VERSION 5.8 ;
BUSBITCHARS "[]" ;
DIVIDERCHAR "/" ;

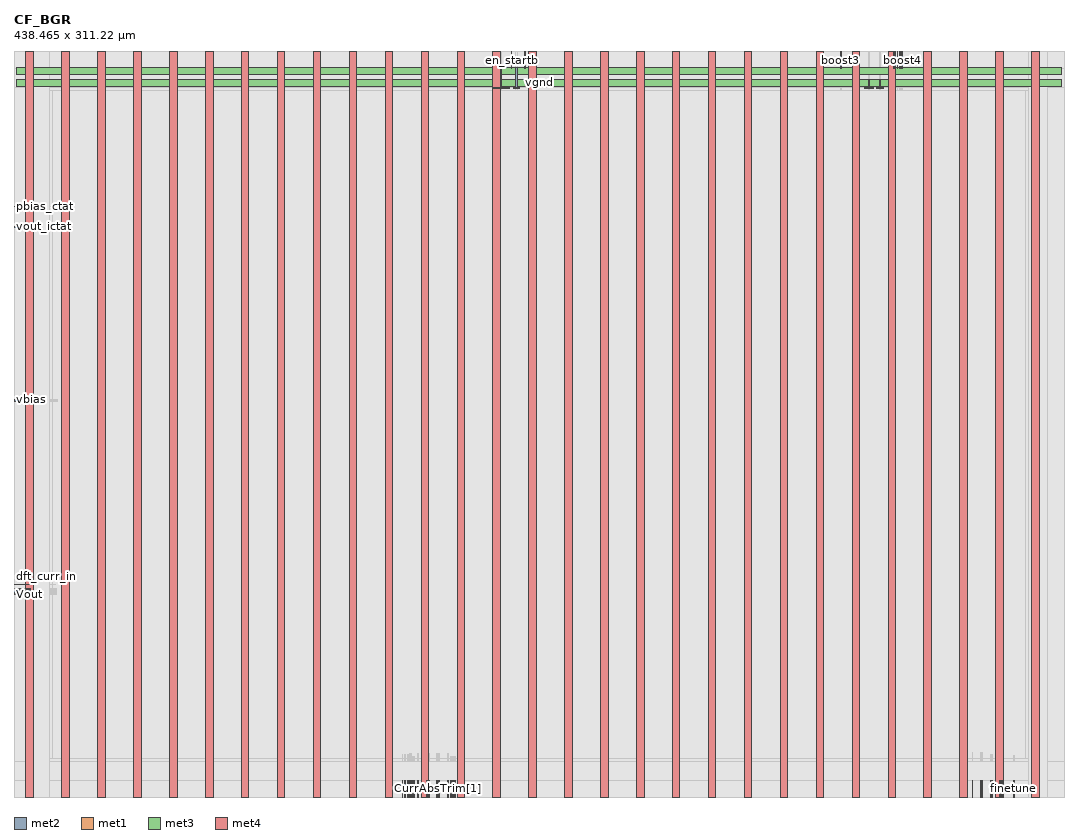
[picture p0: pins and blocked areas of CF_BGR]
MACRO CF_BGR
  CLASS BLOCK ;
  ORIGIN 0 0 ;
  FOREIGN CF_BGR 0 0 ;
  SIZE 438.465 BY 311.22 ;
  PIN CurrAbsTrim[5]
    DIRECTION INPUT ;
    USE SIGNAL ;
    PORT
      LAYER met2 ;
        RECT 181.425 0 181.565 6.9 ;
    END
  END CurrAbsTrim[5]
  PIN finetune
    DIRECTION INPUT ;
    USE SIGNAL ;
    PORT
      LAYER met2 ;
        RECT 417.5 0 417.64 6.9 ;
    END
  END finetune
  PIN boost4
    DIRECTION OUTPUT ;
    USE SIGNAL ;
    PORT
      LAYER met2 ;
        RECT 370.79 304.32 371.11 311.22 ;
    END
  END boost4
  PIN boost7
    DIRECTION OUTPUT ;
    USE SIGNAL ;
    PORT
      LAYER met2 ;
        RECT 369.845 304.32 370.165 311.22 ;
    END
  END boost7
  PIN boost6
    DIRECTION OUTPUT ;
    USE SIGNAL ;
    PORT
      LAYER met2 ;
        RECT 368.765 304.32 369.085 311.22 ;
    END
  END boost6
  PIN boost5
    DIRECTION OUTPUT ;
    USE SIGNAL ;
    PORT
      LAYER met2 ;
        RECT 367.36 304.32 367.68 311.22 ;
    END
  END boost5
  PIN en_startb
    DIRECTION INPUT ;
    USE SIGNAL ;
    PORT
      LAYER met1 ;
        RECT 207.72 304.32 207.86 311.22 ;
    END
  END en_startb
  PIN trimCurr[5]
    DIRECTION INPUT ;
    USE SIGNAL ;
    PORT
      LAYER met2 ;
        RECT 168.295 0 168.435 6.9 ;
    END
  END trimCurr[5]
  PIN trimCurr[4]
    DIRECTION INPUT ;
    USE SIGNAL ;
    PORT
      LAYER met2 ;
        RECT 172.055 0 172.195 6.9 ;
    END
  END trimCurr[4]
  PIN trimCurr[3]
    DIRECTION INPUT ;
    USE SIGNAL ;
    PORT
      LAYER met2 ;
        RECT 172.425 0 172.565 6.9 ;
    END
  END trimCurr[3]
  PIN trimCurr[2]
    DIRECTION INPUT ;
    USE SIGNAL ;
    PORT
      LAYER met2 ;
        RECT 172.795 0 172.935 6.9 ;
    END
  END trimCurr[2]
  PIN trimCurr[0]
    DIRECTION INPUT ;
    USE SIGNAL ;
    PORT
      LAYER met2 ;
        RECT 173.165 0 173.305 6.9 ;
    END
  END trimCurr[0]
  PIN trimCurr[1]
    DIRECTION INPUT ;
    USE SIGNAL ;
    PORT
      LAYER met2 ;
        RECT 176.555 0 176.695 6.9 ;
    END
  END trimCurr[1]
  PIN CurrAbsTrim[0]
    DIRECTION INPUT ;
    USE SIGNAL ;
    PORT
      LAYER met2 ;
        RECT 168.665 0 168.805 6.9 ;
    END
  END CurrAbsTrim[0]
  PIN CurrAbsTrim[1]
    DIRECTION INPUT ;
    USE SIGNAL ;
    PORT
      LAYER met2 ;
        RECT 176.925 0 177.065 6.9 ;
    END
  END CurrAbsTrim[1]
  PIN CurrAbsTrim[2]
    DIRECTION INPUT ;
    USE SIGNAL ;
    PORT
      LAYER met2 ;
        RECT 177.295 0 177.435 6.9 ;
    END
  END CurrAbsTrim[2]
  PIN CurrAbsTrim[3]
    DIRECTION INPUT ;
    USE SIGNAL ;
    PORT
      LAYER met2 ;
        RECT 177.665 0 177.805 6.9 ;
    END
  END CurrAbsTrim[3]
  PIN CurrAbsTrim[4]
    DIRECTION INPUT ;
    USE SIGNAL ;
    PORT
      LAYER met2 ;
        RECT 181.055 0 181.195 6.9 ;
    END
  END CurrAbsTrim[4]
  PIN mux2sel
    DIRECTION INPUT ;
    USE SIGNAL ;
    PORT
      LAYER met2 ;
        RECT 182.16 0 182.3 6.9 ;
    END
  END mux2sel
  PIN mux1sel[0]
    DIRECTION INPUT ;
    USE SIGNAL ;
    PORT
      LAYER met2 ;
        RECT 182.53 0 182.67 6.9 ;
    END
  END mux1sel[0]
  PIN mux1sel[1]
    DIRECTION INPUT ;
    USE SIGNAL ;
    PORT
      LAYER met2 ;
        RECT 182.9 0 183.04 6.9 ;
    END
  END mux1sel[1]
  PIN dft_sel
    DIRECTION INPUT ;
    USE SIGNAL ;
    PORT
      LAYER met2 ;
        RECT 183.27 0 183.41 6.9 ;
    END
  END dft_sel
  PIN pd_ibg
    DIRECTION INPUT ;
    USE SIGNAL ;
    PORT
      LAYER met2 ;
        RECT 183.65 0 183.79 6.9 ;
    END
  END pd_ibg
  PIN pd
    DIRECTION INPUT ;
    USE SIGNAL ;
    PORT
      LAYER met2 ;
        RECT 184.095 0 184.235 6.9 ;
    END
  END pd
  PIN trimTC[6]
    DIRECTION INPUT ;
    USE SIGNAL ;
    PORT
      LAYER met2 ;
        RECT 400.145 0 400.285 6.9 ;
    END
  END trimTC[6]
  PIN trimTC[5]
    DIRECTION INPUT ;
    USE SIGNAL ;
    PORT
      LAYER met2 ;
        RECT 403.535 0 403.675 6.9 ;
    END
  END trimTC[5]
  PIN trimTC[4]
    DIRECTION INPUT ;
    USE SIGNAL ;
    PORT
      LAYER met2 ;
        RECT 404.18 0 404.32 6.9 ;
    END
  END trimTC[4]
  PIN trimTC[3]
    DIRECTION INPUT ;
    USE SIGNAL ;
    PORT
      LAYER met2 ;
        RECT 407.57 0 407.71 6.9 ;
    END
  END trimTC[3]
  PIN trimTC[2]
    DIRECTION INPUT ;
    USE SIGNAL ;
    PORT
      LAYER met2 ;
        RECT 408.27 0 408.41 6.9 ;
    END
  END trimTC[2]
  PIN trimTC[0]
    DIRECTION INPUT ;
    USE SIGNAL ;
    PORT
      LAYER met2 ;
        RECT 411.66 0 411.8 6.9 ;
    END
  END trimTC[0]
  PIN trimTC[1]
    DIRECTION INPUT ;
    USE SIGNAL ;
    PORT
      LAYER met2 ;
        RECT 412.535 0 412.675 6.9 ;
    END
  END trimTC[1]
  PIN inl_ctrl[0]
    DIRECTION INPUT ;
    USE SIGNAL ;
    PORT
      LAYER met2 ;
        RECT 165.955 0 166.095 6.9 ;
    END
  END inl_ctrl[0]
  PIN inl_ctrl[1]
    DIRECTION INPUT ;
    USE SIGNAL ;
    PORT
      LAYER met2 ;
        RECT 165.355 0 165.495 6.9 ;
    END
  END inl_ctrl[1]
  PIN vbias_cascode
    DIRECTION OUTPUT ;
    USE SIGNAL ;
    PORT
      LAYER met2 ;
        RECT 0 164.95 6.9 165.19 ;
    END
  END vbias_cascode
  PIN vbias
    DIRECTION OUTPUT ;
    USE SIGNAL ;
    PORT
      LAYER met2 ;
        RECT 0 165.73 6.9 165.97 ;
    END
  END vbias
  PIN boost3
    DIRECTION OUTPUT ;
    USE SIGNAL ;
    PORT
      LAYER met2 ;
        RECT 345.055 304.32 345.375 311.22 ;
    END
  END boost3
  PIN dft_curr_in
    DIRECTION INPUT ;
    USE SIGNAL ;
    PORT
      LAYER met2 ;
        RECT 0 88.62 6.9 88.86 ;
    END
  END dft_curr_in
  PIN vb2_fast
    DIRECTION INPUT ;
    USE SIGNAL ;
    PORT
      LAYER met1 ;
        RECT 213.215 304.32 213.395 311.22 ;
    END
  END vb2_fast
  PIN Vout
    DIRECTION OUTPUT ;
    USE SIGNAL ;
    PORT
      LAYER met2 ;
        RECT 0 84.56 6.9 84.8 ;
    END
  END Vout
  PIN ibg_3uA
    DIRECTION OUTPUT ;
    USE SIGNAL ;
    PORT
      LAYER met2 ;
        RECT 0 85.06 6.9 85.3 ;
    END
  END ibg_3uA
  PIN ibg_2p375uA
    DIRECTION OUTPUT ;
    USE SIGNAL ;
    PORT
      LAYER met2 ;
        RECT 0 85.5 6.9 85.74 ;
    END
  END ibg_2p375uA
  PIN mux1out
    DIRECTION OUTPUT ;
    USE SIGNAL ;
    PORT
      LAYER met2 ;
        RECT 0 86.03 6.9 86.27 ;
    END
  END mux1out
  PIN mux2out
    DIRECTION OUTPUT ;
    USE SIGNAL ;
    PORT
      LAYER met2 ;
        RECT 0 86.825 6.9 87.065 ;
    END
  END mux2out
  PIN ictat
    DIRECTION OUTPUT ;
    USE SIGNAL ;
    PORT
      LAYER met2 ;
        RECT 166.615 0 166.755 6.9 ;
    END
  END ictat
  PIN iptat
    DIRECTION OUTPUT ;
    USE SIGNAL ;
    PORT
      LAYER met2 ;
        RECT 167.22 0 167.36 6.9 ;
    END
  END iptat
  PIN inl_ctrl[6]
    DIRECTION INPUT ;
    USE SIGNAL ;
    PORT
      LAYER met2 ;
        RECT 162.285 0 162.425 6.9 ;
    END
  END inl_ctrl[6]
  PIN inl_ctrl[5]
    DIRECTION INPUT ;
    USE SIGNAL ;
    PORT
      LAYER met2 ;
        RECT 162.9 0 163.04 6.9 ;
    END
  END inl_ctrl[5]
  PIN vgnd
    DIRECTION INPUT ;
    USE GROUND ;
    PORT
      LAYER met1 ;
        RECT 355.21 295.82 358.78 296.22 ;
      LAYER met2 ;
        RECT 356.755 295.82 357.235 299.82 ;
      LAYER met1 ;
        RECT 360.205 295.82 362.975 296.22 ;
      LAYER met2 ;
        RECT 361.35 295.82 361.83 299.82 ;
      LAYER met3 ;
        RECT 1.23 296.72 437.235 299.82 ;
      LAYER met4 ;
        RECT 20 0 23.1 311.22 ;
        RECT 50 0 53.1 311.22 ;
        RECT 80 0 83.1 311.22 ;
        RECT 110 0 113.1 311.22 ;
        RECT 140 0 143.1 311.22 ;
        RECT 170 0 173.1 311.22 ;
        RECT 200 0 203.1 311.22 ;
        RECT 230 0 233.1 311.22 ;
        RECT 260 0 263.1 311.22 ;
        RECT 290 0 293.1 311.22 ;
        RECT 320 0 323.1 311.22 ;
        RECT 350 0 353.1 311.22 ;
        RECT 380 0 383.1 311.22 ;
        RECT 410 0 413.1 311.22 ;
    END
  END vgnd
  PIN vpwr
    DIRECTION INPUT ;
    USE POWER ;
    PORT
      LAYER met1 ;
        RECT 199.955 295.82 207.08 296.22 ;
      LAYER met2 ;
        RECT 203.28 295.82 203.76 304.62 ;
      LAYER met1 ;
        RECT 208.455 295.82 211.235 296.22 ;
      LAYER met2 ;
        RECT 209.605 295.82 210.085 304.62 ;
      LAYER met3 ;
        RECT 1.23 301.52 437.235 304.62 ;
      LAYER met4 ;
        RECT 5 0 8.1 311.22 ;
        RECT 35 0 38.1 311.22 ;
        RECT 65 0 68.1 311.22 ;
        RECT 95 0 98.1 311.22 ;
        RECT 125 0 128.1 311.22 ;
        RECT 155 0 158.1 311.22 ;
        RECT 185 0 188.1 311.22 ;
        RECT 215 0 218.1 311.22 ;
        RECT 245 0 248.1 311.22 ;
        RECT 275 0 278.1 311.22 ;
        RECT 305 0 308.1 311.22 ;
        RECT 335 0 338.1 311.22 ;
        RECT 365 0 368.1 311.22 ;
        RECT 395 0 398.1 311.22 ;
        RECT 425 0 428.1 311.22 ;
    END
  END vpwr
  PIN inl_ctrl[3]
    DIRECTION INPUT ;
    USE SIGNAL ;
    PORT
      LAYER met2 ;
        RECT 164.12 0 164.26 6.9 ;
    END
  END inl_ctrl[3]
  PIN inl_ctrl[2]
    DIRECTION INPUT ;
    USE SIGNAL ;
    PORT
      LAYER met2 ;
        RECT 164.725 0 164.865 6.9 ;
    END
  END inl_ctrl[2]
  PIN pbias_ctat
    DIRECTION OUTPUT ;
    USE SIGNAL ;
    PORT
      LAYER met2 ;
        RECT 0 246.41 6.9 246.65 ;
    END
  END pbias_ctat
  PIN vout_ictat
    DIRECTION OUTPUT ;
    USE SIGNAL ;
    PORT
      LAYER met2 ;
        RECT 0 237.98 6.9 238.22 ;
    END
  END vout_ictat
  PIN inl_ctrl[4]
    DIRECTION INPUT ;
    USE SIGNAL ;
    PORT
      LAYER met2 ;
        RECT 163.505 0 163.645 6.9 ;
    END
  END inl_ctrl[4]
  OBS
    LAYER li1 ;
      RECT 0 304.32 438.465 311.22 ;
      RECT 0 0 438.465 6.9 ;
      RECT 0 0 6.9 311.22 ;
      RECT 431.565 0 438.465 311.22 ;
    LAYER met1 ;
      RECT 0 304.32 15 311.22 ;
      RECT 0 0 15 6.9 ;
      RECT 0 0 6.9 311.22 ;
      RECT 423.465 304.32 438.465 311.22 ;
      RECT 423.465 0 438.465 6.9 ;
      RECT 431.565 0 438.465 311.22 ;
      RECT 15 0 423.465 6.9 ;
      RECT 15 304.32 207.72 311.22 ;
      RECT 207.86 304.32 213.215 311.22 ;
      RECT 213.395 304.32 423.465 311.22 ;
    LAYER met2 ;
      RECT 0 0 15 6.9 ;
      RECT 0 0 6.9 84.56 ;
      RECT 0 84.8 6.9 85.06 ;
      RECT 0 85.3 6.9 85.5 ;
      RECT 0 85.74 6.9 86.03 ;
      RECT 0 86.27 6.9 86.825 ;
      RECT 0 87.065 6.9 88.62 ;
      RECT 0 88.86 6.9 164.95 ;
      RECT 0 165.19 6.9 165.73 ;
      RECT 0 165.97 6.9 237.98 ;
      RECT 0 238.22 6.9 246.41 ;
      RECT 0 304.32 15 311.22 ;
      RECT 0 246.65 6.9 311.22 ;
      RECT 423.465 304.32 438.465 311.22 ;
      RECT 423.465 0 438.465 6.9 ;
      RECT 431.565 0 438.465 311.22 ;
      RECT 15 0 162.285 6.9 ;
      RECT 162.425 0 162.9 6.9 ;
      RECT 163.04 0 163.505 6.9 ;
      RECT 163.645 0 164.12 6.9 ;
      RECT 164.26 0 164.725 6.9 ;
      RECT 164.865 0 165.355 6.9 ;
      RECT 165.495 0 165.955 6.9 ;
      RECT 166.095 0 166.615 6.9 ;
      RECT 166.755 0 167.22 6.9 ;
      RECT 167.36 0 168.295 6.9 ;
      RECT 168.435 0 168.665 6.9 ;
      RECT 168.805 0 172.055 6.9 ;
      RECT 172.195 0 172.425 6.9 ;
      RECT 172.565 0 172.795 6.9 ;
      RECT 172.935 0 173.165 6.9 ;
      RECT 173.305 0 176.555 6.9 ;
      RECT 176.695 0 176.925 6.9 ;
      RECT 177.065 0 177.295 6.9 ;
      RECT 177.435 0 177.665 6.9 ;
      RECT 177.805 0 181.055 6.9 ;
      RECT 181.195 0 181.425 6.9 ;
      RECT 181.565 0 182.16 6.9 ;
      RECT 182.3 0 182.53 6.9 ;
      RECT 182.67 0 182.9 6.9 ;
      RECT 183.04 0 183.27 6.9 ;
      RECT 183.41 0 183.65 6.9 ;
      RECT 183.79 0 184.095 6.9 ;
      RECT 184.235 0 400.145 6.9 ;
      RECT 400.285 0 403.535 6.9 ;
      RECT 403.675 0 404.18 6.9 ;
      RECT 404.32 0 407.57 6.9 ;
      RECT 407.71 0 408.27 6.9 ;
      RECT 408.41 0 411.66 6.9 ;
      RECT 411.8 0 412.535 6.9 ;
      RECT 412.675 0 417.5 6.9 ;
      RECT 417.64 0 423.465 6.9 ;
      RECT 15 304.32 203.28 311.22 ;
      RECT 203.28 304.62 203.76 311.22 ;
      RECT 203.76 304.32 209.605 311.22 ;
      RECT 209.605 304.62 210.085 311.22 ;
      RECT 210.085 304.32 345.055 311.22 ;
      RECT 345.375 304.32 356.755 311.22 ;
      RECT 356.755 304.32 357.235 311.22 ;
      RECT 357.235 304.32 361.35 311.22 ;
      RECT 361.35 304.32 361.83 311.22 ;
      RECT 361.83 304.32 367.36 311.22 ;
      RECT 367.68 304.32 368.765 311.22 ;
      RECT 369.085 304.32 369.845 311.22 ;
      RECT 370.165 304.32 370.79 311.22 ;
      RECT 371.11 304.32 423.465 311.22 ;
    # inner-halo seal
    LAYER li1 ;
      RECT 6.9 6.9 431.565 304.32 ;
      RECT 0 296.22 438.465 304.32 ;
      RECT 0 6.9 438.465 15 ;
      RECT 6.9 0 15 311.22 ;
      RECT 423.465 0 431.565 311.22 ;
    LAYER met1 ;
      RECT 207.72 295.035 207.86 304.32 ;
      RECT 213.215 295.01 213.395 304.32 ;
      RECT 6.9 6.9 16 304.32 ;
      RECT 422.465 6.9 431.565 304.32 ;
      RECT 15 6.9 423.465 16 ;
      RECT 15 295.22 199.955 304.32 ;
      RECT 199.955 295.22 207.08 295.82 ;
      RECT 199.955 296.22 207.08 304.32 ;
      RECT 207.08 295.22 207.72 304.32 ;
      RECT 207.86 295.22 208.455 304.32 ;
      RECT 208.455 295.22 211.235 295.82 ;
      RECT 208.455 296.22 211.235 304.32 ;
      RECT 211.235 295.22 213.215 304.32 ;
      RECT 213.395 295.22 355.21 304.32 ;
      RECT 355.21 295.22 358.78 295.82 ;
      RECT 355.21 296.22 358.78 304.32 ;
      RECT 358.78 295.22 360.205 304.32 ;
      RECT 360.205 295.22 362.975 295.82 ;
      RECT 360.205 296.22 362.975 304.32 ;
      RECT 362.975 295.22 423.465 304.32 ;
      RECT 0 296.22 438.465 304.32 ;
      RECT 0 6.9 438.465 15 ;
      RECT 6.9 0 15 311.22 ;
      RECT 423.465 0 431.565 311.22 ;
    LAYER met2 ;
      RECT 181.425 6.9 181.565 18.055 ;
      RECT 417.5 6.9 417.64 17.22 ;
      RECT 370.79 295.025 371.11 304.32 ;
      RECT 369.845 295.025 370.165 304.32 ;
      RECT 368.765 295.035 369.085 304.32 ;
      RECT 367.36 295.045 367.68 304.32 ;
      RECT 168.295 6.9 168.435 18.055 ;
      RECT 172.055 6.9 172.195 18.055 ;
      RECT 172.425 6.9 172.565 18.055 ;
      RECT 172.795 6.9 172.935 18.055 ;
      RECT 173.165 6.9 173.305 18.055 ;
      RECT 176.555 6.9 176.695 18.055 ;
      RECT 168.665 6.9 168.805 18.055 ;
      RECT 176.925 6.9 177.065 18.055 ;
      RECT 177.295 6.9 177.435 18.055 ;
      RECT 177.665 6.9 177.805 18.055 ;
      RECT 181.055 6.9 181.195 18.055 ;
      RECT 182.16 6.9 182.3 17.035 ;
      RECT 182.53 6.9 182.67 17.035 ;
      RECT 182.9 6.9 183.04 17.035 ;
      RECT 183.27 6.9 183.41 17.035 ;
      RECT 183.65 6.9 183.79 17.035 ;
      RECT 184.095 6.9 184.235 17.035 ;
      RECT 400.145 6.9 400.285 18.375 ;
      RECT 403.535 6.9 403.675 18.375 ;
      RECT 404.18 6.9 404.32 18.375 ;
      RECT 407.57 6.9 407.71 17.77 ;
      RECT 408.27 6.9 408.41 17.77 ;
      RECT 411.66 6.9 411.8 17.465 ;
      RECT 412.535 6.9 412.675 17.22 ;
      RECT 165.955 6.9 166.095 18.055 ;
      RECT 165.355 6.9 165.495 18.055 ;
      RECT 6.9 164.95 18.075 165.19 ;
      RECT 6.9 165.73 18.075 165.97 ;
      RECT 345.055 295.05 345.375 304.32 ;
      RECT 6.9 88.62 17.495 88.86 ;
      RECT 6.9 84.56 17.75 84.8 ;
      RECT 6.9 85.06 17.75 85.3 ;
      RECT 6.9 85.5 17.75 85.74 ;
      RECT 6.9 86.03 17.75 86.27 ;
      RECT 6.9 86.825 17.75 87.065 ;
      RECT 166.615 6.9 166.755 17.035 ;
      RECT 167.22 6.9 167.36 17.035 ;
      RECT 162.285 6.9 162.425 17.945 ;
      RECT 162.9 6.9 163.04 17.935 ;
      RECT 164.12 6.9 164.26 17.935 ;
      RECT 164.725 6.9 164.865 17.945 ;
      RECT 6.9 246.41 18.49 246.65 ;
      RECT 6.9 237.98 17.015 238.22 ;
      RECT 163.505 6.9 163.645 17.945 ;
      RECT 6.9 6.9 16 84.56 ;
      RECT 6.9 84.8 16 85.06 ;
      RECT 6.9 85.3 16 85.5 ;
      RECT 6.9 85.74 16 86.03 ;
      RECT 6.9 86.27 16 86.825 ;
      RECT 6.9 87.065 16 88.62 ;
      RECT 6.9 88.86 16 164.95 ;
      RECT 6.9 165.19 16 165.73 ;
      RECT 6.9 165.97 16 237.98 ;
      RECT 6.9 238.22 16 246.41 ;
      RECT 6.9 246.65 16 304.32 ;
      RECT 422.465 6.9 431.565 304.32 ;
      RECT 15 6.9 162.285 16 ;
      RECT 162.425 6.9 162.9 16 ;
      RECT 163.04 6.9 163.505 16 ;
      RECT 163.645 6.9 164.12 16 ;
      RECT 164.26 6.9 164.725 16 ;
      RECT 164.865 6.9 165.355 16 ;
      RECT 165.495 6.9 165.955 16 ;
      RECT 166.095 6.9 166.615 16 ;
      RECT 166.755 6.9 167.22 16 ;
      RECT 167.36 6.9 168.295 16 ;
      RECT 168.435 6.9 168.665 16 ;
      RECT 168.805 6.9 172.055 16 ;
      RECT 172.195 6.9 172.425 16 ;
      RECT 172.565 6.9 172.795 16 ;
      RECT 172.935 6.9 173.165 16 ;
      RECT 173.305 6.9 176.555 16 ;
      RECT 176.695 6.9 176.925 16 ;
      RECT 177.065 6.9 177.295 16 ;
      RECT 177.435 6.9 177.665 16 ;
      RECT 177.805 6.9 181.055 16 ;
      RECT 181.195 6.9 181.425 16 ;
      RECT 181.565 6.9 182.16 16 ;
      RECT 182.3 6.9 182.53 16 ;
      RECT 182.67 6.9 182.9 16 ;
      RECT 183.04 6.9 183.27 16 ;
      RECT 183.41 6.9 183.65 16 ;
      RECT 183.79 6.9 184.095 16 ;
      RECT 184.235 6.9 400.145 16 ;
      RECT 400.285 6.9 403.535 16 ;
      RECT 403.675 6.9 404.18 16 ;
      RECT 404.32 6.9 407.57 16 ;
      RECT 407.71 6.9 408.27 16 ;
      RECT 408.41 6.9 411.66 16 ;
      RECT 411.8 6.9 412.535 16 ;
      RECT 412.675 6.9 417.5 16 ;
      RECT 417.64 6.9 423.465 16 ;
      RECT 15 295.22 203.28 304.32 ;
      RECT 203.76 295.22 209.605 304.32 ;
      RECT 210.085 295.22 345.055 304.32 ;
      RECT 345.375 295.22 356.755 304.32 ;
      RECT 356.755 299.82 357.235 304.32 ;
      RECT 357.235 295.22 361.35 304.32 ;
      RECT 361.35 299.82 361.83 304.32 ;
      RECT 361.83 295.22 367.36 304.32 ;
      RECT 367.68 295.22 368.765 304.32 ;
      RECT 369.085 295.22 369.845 304.32 ;
      RECT 370.165 295.22 370.79 304.32 ;
      RECT 371.11 295.22 423.465 304.32 ;
      RECT 0 296.22 203.28 304.32 ;
      RECT 203.76 296.22 209.605 304.32 ;
      RECT 210.085 296.22 356.755 304.32 ;
      RECT 356.755 299.82 357.235 304.32 ;
      RECT 357.235 296.22 361.35 304.32 ;
      RECT 361.35 299.82 361.83 304.32 ;
      RECT 361.83 296.22 438.465 304.32 ;
      RECT 0 6.9 438.465 15 ;
      RECT 6.9 0 15 311.22 ;
      RECT 423.465 0 431.565 311.22 ;
  END
END CF_BGR

END LIBRARY
